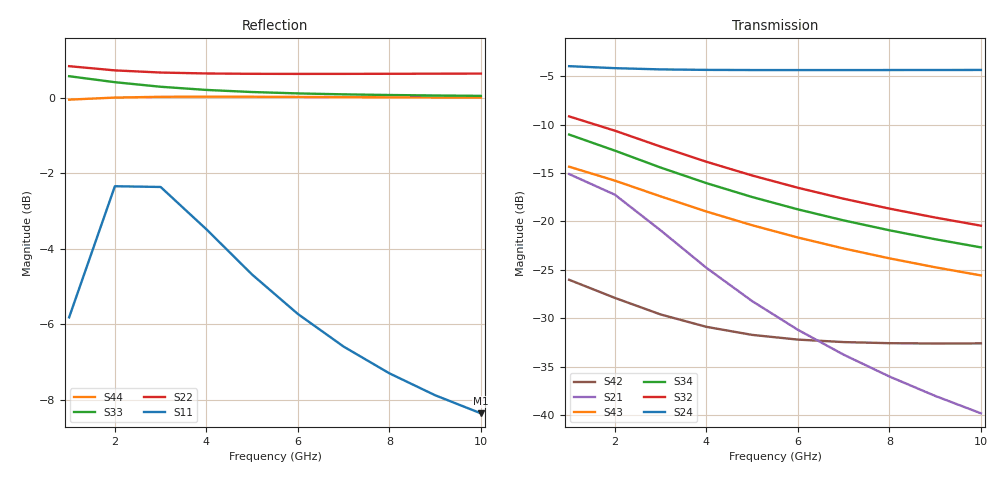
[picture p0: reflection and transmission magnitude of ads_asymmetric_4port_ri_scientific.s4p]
! Created Fri Aug 21 13:29:00 2026
# ghz S ri R 50
! 4 Port Network Data from SP1.SP block
! freq  reS11  imS11  reS12  imS12  reS13  imS13  reS14  imS14
!  reS21  imS21  reS22  imS22  reS23  imS23  reS24  imS24
!  reS31  imS31  reS32  imS32  reS33  imS33  reS34  imS34
!  reS41  imS41  reS42  imS42  reS43  imS43  reS44  imS44
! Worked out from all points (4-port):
!   10 points, 1 GHz to 10 GHz, reference 50 ohm
!   strongest paths, dB at 1 GHz, 3 GHz, 6 GHz, 8 GHz, 10 GHz:
!     S24: -4.0, -4.3, -4.4, -4.4, -4.4
!     S32: -9.2, -12.3, -16.5, -18.7, -20.4
!     S34: -11.0, -14.4, -18.8, -20.9, -22.7
!     S43: -14.4, -17.4, -21.7, -23.8, -25.6
!     S21: -15.1, -20.9, -31.2, -36.0, -39.8
!     S42: -26.0, -29.6, -32.2, -32.6, -32.6
!   lowest |S11| = -8.4 dB at 10 GHz (marker M1), VSWR 2.23, Z = 29.1 - j23.5 ohm
!   |S11| at or under -10 dB: nowhere
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1  0.4873 0.1553  0.00514 0.0155  0.03 -0.0216  0.00735 0.0483
   0.00252 0.1754  -1.097 0.0856  -0.1011 0.2085  -0.3231 0.5443
   0.0197 0.0877  -0.306 0.1664  -0.7688 0.74  -0.0323 0.2788
   0.0038 -0.0139  0.0499 -0.00174  0.1713 -0.0855  -0.9934 -0.0174
2  0.7455 -0.1624  0.00672 0.00594  -0.0016 -0.0248  0.0275 0.0274
   0.0913 0.1025  -1.083 0.0822  -0.0334 0.1967  -0.3116 0.5339
   0.056 0.0214  -0.2102 0.2054  -0.2715 1.012  0.0386 0.2285
   -0.00259 -0.00743  0.0401 -0.00364  0.1204 -0.1088  -0.9998 -0.0114
3  0.5658 -0.5093  0.00518 0.00199  -0.00973 -0.00956  0.0251 0.00715
   0.0853 0.0281  -1.077 0.0755  0.00531 0.1673  -0.3113 0.5236
   0.0308 -0.0114  -0.1384 0.2  0.127 1.026  0.0658 0.1778
   -0.00268 -0.00306  0.033 -0.00225  0.0808 -0.1076  -1.002 -0.00584
4  0.3056 -0.5953  0.0036 0.000494  -0.007 -0.00224  0.0171 -0.000765
   0.0575 -0.00031  -1.074 0.0697  0.0242 0.1385  -0.3142 0.5178
   0.0121 -0.0128  -0.0925 0.1808  0.3914 0.9456  0.073 0.1396
   -0.00174 -0.00147  0.0285 0.000152  0.055 -0.098  -1.003 -0.0018
6  0.0151 -0.5166  0.00184 -0.000229  -0.00254 0.000515  0.00774 -0.00313
   0.026 -0.00912  -1.073 0.0621  0.0352 0.0974  -0.3195 0.5129
   0.00156 -0.00602  -0.0455 0.142  0.6723 0.7572  0.0687 0.0926
   -0.000815 -0.000627  0.0241 0.00452  0.0282 -0.0775  -1.002 0.00308
8  -0.1043 -0.4184  0.00107 -0.000291  -0.00104 0.00052  0.00411 -0.00254
   0.0139 -0.00757  -1.074 0.0578  0.0349 0.0729  -0.3229 0.5111
   -1.75e-05 -0.00279  -0.0251 0.1136  0.8005 0.6121  0.0598 0.0671
   -0.000487 -0.000374  0.0222 0.00757  0.0163 -0.0623  -1.001 0.00567
10  -0.1617 -0.3458  0.000688 -0.000256  -0.000498 0.000358  0.00249 -0.00191
    0.00844 -0.00571  -1.074 0.0551  0.0321 0.0576  -0.3251 0.5104
    -0.000239 -0.00145  -0.0149 0.0938  0.8671 0.5084  0.0519 0.0519
    -0.000332 -0.00025  0.0213 0.00967  0.0103 -0.0516  -0.9998 0.0072
